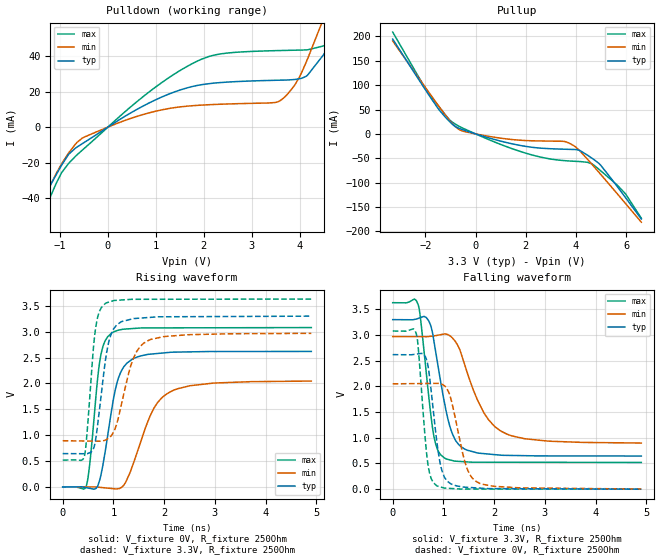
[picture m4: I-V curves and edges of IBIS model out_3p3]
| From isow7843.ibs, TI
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|   out_3p3 Model
[Model]   out_3p3
Model_type   Output
Polarity   Non-Inverting
Vmeas = 1.65
Vref = 3.3
Cref = 2pF
Rref = 250
|   typ   min   max
C_comp   1.000e-200   NA   NA
|C_comp (ON state)   1.000e-200   NA   NA
|C_comp (OFF state)   1.000e-200   NA   NA
[Voltage Range]   3.3   2.97   3.63
[Temperature Range]   27   150   -55
[Pullup Reference]   3.3   2.97   3.63
[Pulldown Reference]   0   0   0
[Power Clamp Reference]   3.3   2.97   3.63
[GND Clamp Reference]   0   0   0
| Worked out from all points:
|   slope of the pulldown table from 0 to 0.495 V, typ, clamps not added: 59.5 ohm
|   slope of the pullup table from 0 to 0.495 V, typ, clamps not added: 63.9 ohm
|   falling waveform, V_fixture 3.3V, R_fixture 250Ohm: 20-80 % time 310ps typ, 550ps min, 210ps max; typ from 3.3 V to 0.645 V
|   rising waveform, V_fixture 0V, R_fixture 250Ohm: 20-80 % time 286ps typ, 501ps min, 185ps max; typ from 0 V to 2.62 V
|   rising waveform, V_fixture 3.3V, R_fixture 250Ohm: 20-80 % time 215ps typ, 335ps min, 153ps max; typ from 0.645 V to 3.3 V
|   falling waveform, V_fixture 0V, R_fixture 250Ohm: 20-80 % time 194ps typ, 285ps min, 150ps max; typ from 2.62 V to 0 V
[Pulldown]
|   Voltage   I(typ)   I(min)   I(max)
-3.3V     -169.6mA   -158.2mA   -192.9mA
-1.657V   -57.2mA    -59.07mA   -68.54mA
-1.439V   -44.94mA   -46.35mA   -54.56mA
-963.6mV  -21.45mA   -20.69mA   -25.7mA
-537.9mV  -9.424mA   -6.298mA   -13.11mA
848.1mV   13.5mA     7.98mA     19.62mA
1.957V    23.99mA    12.45mA    38.4mA
3.62V     26.54mA    15.46mA    43.28mA
4.125V    28.6mA     36.1mA     43.6mA
4.491V    40.71mA    61.04mA    45.82mA
4.877V    59.19mA    88.66mA    57.35mA
6.6V      194.5mA    215.1mA    179.3mA
[Pullup]
|   Voltage   I(typ)   I(min)   I(max)
-3.3V     194.5mA    190.7mA    208.9mA
-1.914V   84mA       89mA       87.05mA
-953.7mV  21.12mA    22.59mA    25.09mA
-498.3mV  8.34mA     5.505mA    11.53mA
1.403V    -19.79mA   -11.32mA   -29.41mA
2.65V     -29.47mA   -14.57mA   -48.3mA
3.759V    -31.77mA   -19.87mA   -55.7mA
4.135V    -33.77mA   -34.04mA   -56.72mA
4.709V    -52.58mA   -66.84mA   -64.2mA
4.986V    -64.56mA   -83.34mA   -75.85mA
5.976V    -131.2mA   -143.2mA   -123.3mA
6.6V      -174.6mA   -181.2mA   -173.1mA
[Ramp]
R_load = 250
|   typ   min   max
dV/dt_r   1.57124/2.84879e-10   1.2279/4.99553e-10   1.8475/1.84774e-10
dV/dt_f   1.59288/3.08677e-10   1.24336/5.4405e-10   1.86625/2.09546e-10
[Falling Waveform]
V_fixture = 3.3V
V_fixture_min = 2.97V
V_fixture_max = 3.63V
R_fixture = 250Ohm
C_fixture = 0F
|   Time   V(typ)   V(min)   V(max)
0s        3.3V       2.97V      3.63V
498.8ps   3.322V     2.968V     3.6V
660ps     3.342V     2.968V     2.279V
802.4ps   2.941V     2.981V     1.084V
1.017ns   1.699V     3.021V     607.9mV
1.172ns   1.088V     2.949V     558.4mV
1.316ns   853.7mV    2.73V      540mV
1.781ns   693.2mV    1.517V     524.6mV
2.127ns   661.5mV    1.133V     524.1mV
4.9ns     645.2mV    897.7mV    519.6mV
[Rising Waveform]
V_fixture = 0V
V_fixture_min = 0V
V_fixture_max = 0V
R_fixture = 250Ohm
C_fixture = 0F
|   Time   V(typ)   V(min)   V(max)
0s        3.967nV    223.2nV    2.291nV
464.6ps   -13.46mV   1.748mV    14.94mV
540.1ps   -27.82mV   2.033mV    507.2mV
738.8ps   167.5mV    -7.444mV   2.477V
967ps     1.505V     -29.2mV    2.975V
1.099ns   2.108V     -32.1mV    3.029V
1.268ns   2.395V     150.3mV    3.053V
1.781ns   2.571V     1.491V     3.073V
2.166ns   2.604V     1.861V     3.074V
4.9ns     2.619V     2.046V     3.079V
[Rising Waveform]
V_fixture = 3.3V
V_fixture_min = 2.97V
V_fixture_max = 3.63V
R_fixture = 250Ohm
C_fixture = 0F
|   Time   V(typ)   V(min)   V(max)
0s        645.2mV    893.8mV    519.6mV
425.7ps   642.7mV    888.5mV    587.5mV
641.9ps   874.2mV    885.9mV    3.022V
715ps     1.415V     885mV      3.369V
839ps     2.429V     905.9mV    3.544V
949.9ps   2.941V     982.6mV    3.583V
1.062ns   3.128V     1.213V     3.606V
1.383ns   3.249V     2.461V     3.625V
1.695ns   3.274V     2.834V     3.626V
4.9ns     3.3V       2.968V     3.63V
[Falling Waveform]
|Gnd
V_fixture = 0V
V_fixture_min = 0V
V_fixture_max = 0V
R_fixture = 250Ohm
C_fixture = 0F
|   Time   V(typ)   V(min)   V(max)
0s        2.619V     2.05V      3.079V
462.5ps   2.629V     2.055V     3.033V
506.7ps   2.635V     2.055V     2.717V
689ps     2.434V     2.057V     520.8mV
859.9ps   1.001V     2.059V     72.52mV
949.9ps   437.4mV    2.048V     40.21mV
1.074ns   156.4mV    1.944V     17.97mV
1.453ns   36.77mV    435.1mV    3.359mV
1.717ns   20.74mV    111.8mV    3.102mV
4.9ns     23.9uV     2.019mV    -116.1nV
